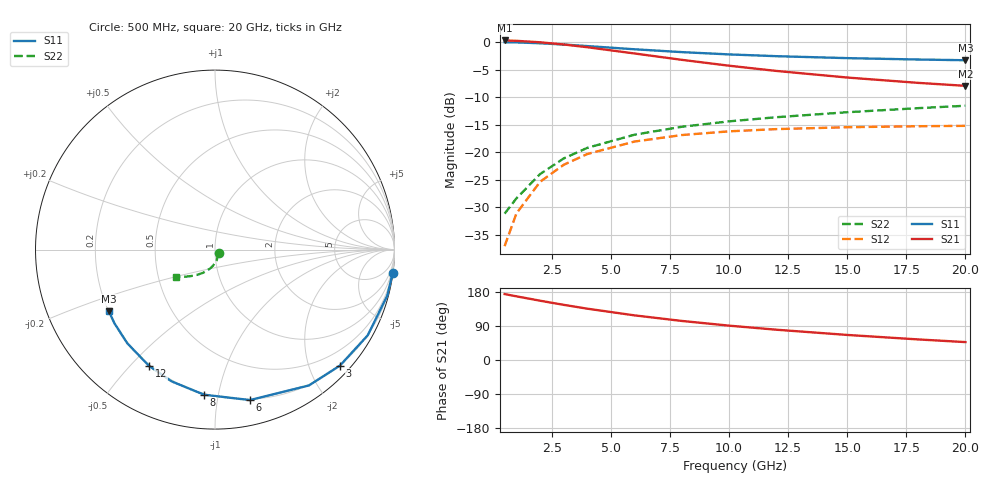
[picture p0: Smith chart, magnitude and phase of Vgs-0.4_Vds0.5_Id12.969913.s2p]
# Hz S RI R 50
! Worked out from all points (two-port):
!   12 points, 500 MHz to 20 GHz, reference 50 ohm
!   highest |S21| = 0.30 dB at 500 MHz (marker M1); lowest = -7.9 dB at 20 GHz (marker M2)
!   |S21| within 3 dB of the highest: start of sweep to 7.098 GHz
!   lowest |S11| = -3.3 dB at 20 GHz (marker M3), VSWR 5.33, Z = 10 - j13 ohm
!   |S11| at or under -10 dB: nowhere
!   |S22| runs from -31.2 to -11.6 dB; largest |S21 - S12| = 1
!   S11 on the Smith chart (normalised r, x): 500 MHz: 0, -15; 3 GHz: 0.19, -2.53; 6 GHz: 0.19, -1.24; 8 GHz: 0.19, -0.91; 12 GHz: 0.19, -0.57; 20 GHz: 0.20, -0.26
5e8  0.9899 -0.1299  -1.029 0.1082  0.00118 0.014  0.022 -0.0168
1e9  0.9602 -0.2553  -1.004 0.2127  0.00466 0.0274  0.0189 -0.0331
2e9  0.8509 -0.4776  -0.9132 0.3978  0.0175 0.0509  0.00736 -0.0629
3e9  0.6962 -0.6463  -0.7844 0.5382  0.0355 0.0681  -0.00914 -0.0872
4e9  0.5226 -0.7572  -0.6399 0.6303  0.0557 0.0785  -0.028 -0.1059
6e9  0.1945 -0.8382  -0.3671 0.6973  0.0937 0.0827  -0.0651 -0.1287
8e9  -0.0605 -0.8086  -0.1559 0.6721  0.1226 0.0739  -0.0969 -0.14
1e10  -0.2415 -0.7343  -0.00686 0.6101  0.1426 0.06  -0.123 -0.1456
1.2e10  -0.3673 -0.6479  0.0958 0.5387  0.1557 0.0449  -0.145 -0.1489
1.5e10  -0.4884 -0.5223  0.1929 0.4358  0.167 0.0231  -0.1739 -0.1516
1.8e10  -0.5602 -0.4108  0.2488 0.3462  0.1721 0.00346  -0.2 -0.1521
2e10  -0.5911 -0.3447  0.2719 0.2942  0.1733 -0.00835  -0.2167 -0.1511
